VERSION 5.4 ;
NAMESCASESENSITIVE ON ;
BUSBITCHARS "[]" ;
DIVIDERCHAR "/" ;
UNITS
  DATABASE MICRONS 2000 ;
END UNITS
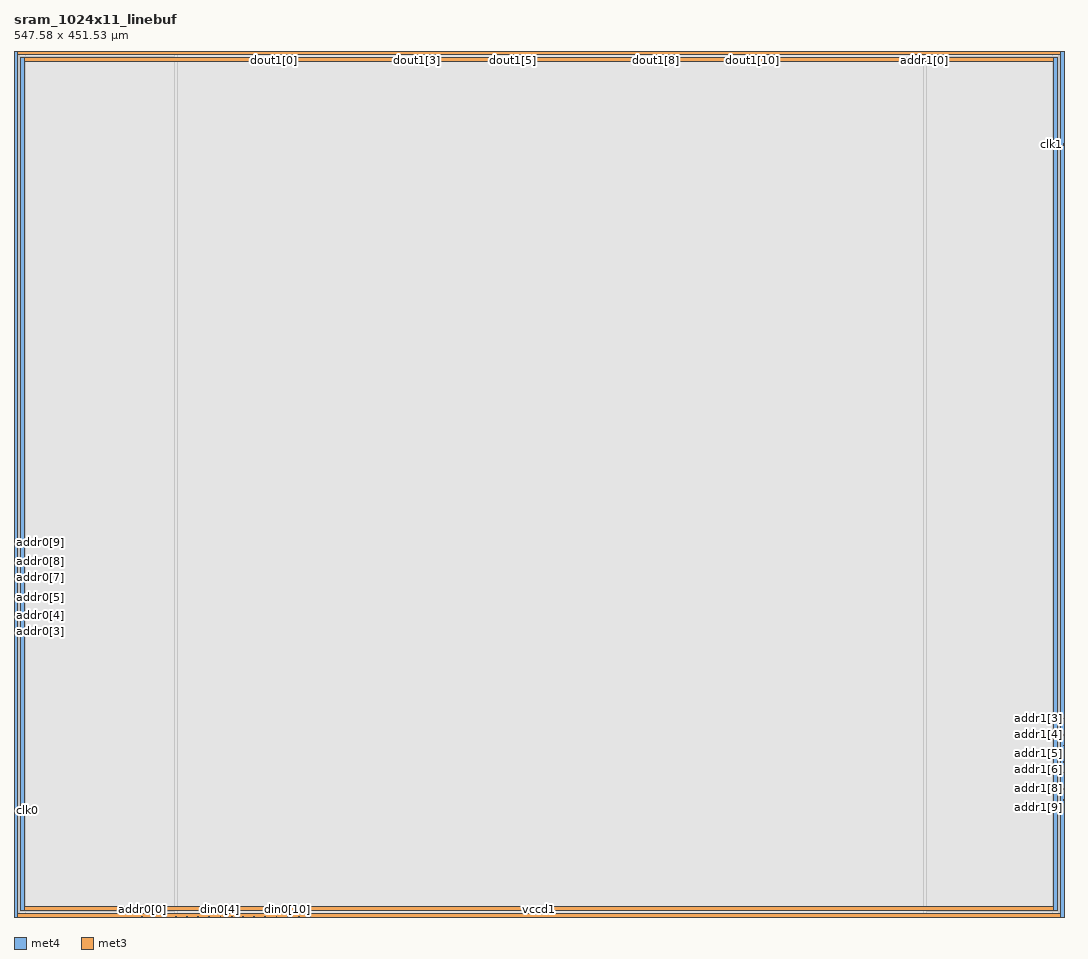
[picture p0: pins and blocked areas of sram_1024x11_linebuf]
MACRO sram_1024x11_linebuf
   CLASS BLOCK ;
   SIZE 547.58 BY 451.53 ;
   SYMMETRY X Y R90 ;
   PIN din0[0]
      DIRECTION INPUT ;
      PORT
         LAYER met4 ;
         RECT  84.14 0.0 84.52 0.38 ;
      END
   END din0[0]
   PIN din0[1]
      DIRECTION INPUT ;
      PORT
         LAYER met4 ;
         RECT  89.98 0.0 90.36 0.38 ;
      END
   END din0[1]
   PIN din0[2]
      DIRECTION INPUT ;
      PORT
         LAYER met4 ;
         RECT  95.82 0.0 96.2 0.38 ;
      END
   END din0[2]
   PIN din0[3]
      DIRECTION INPUT ;
      PORT
         LAYER met4 ;
         RECT  101.66 0.0 102.04 0.38 ;
      END
   END din0[3]
   PIN din0[4]
      DIRECTION INPUT ;
      PORT
         LAYER met4 ;
         RECT  107.5 0.0 107.88 0.38 ;
      END
   END din0[4]
   PIN din0[5]
      DIRECTION INPUT ;
      PORT
         LAYER met4 ;
         RECT  113.34 0.0 113.72 0.38 ;
      END
   END din0[5]
   PIN din0[6]
      DIRECTION INPUT ;
      PORT
         LAYER met4 ;
         RECT  119.18 0.0 119.56 0.38 ;
      END
   END din0[6]
   PIN din0[7]
      DIRECTION INPUT ;
      PORT
         LAYER met4 ;
         RECT  125.02 0.0 125.4 0.38 ;
      END
   END din0[7]
   PIN din0[8]
      DIRECTION INPUT ;
      PORT
         LAYER met4 ;
         RECT  130.86 0.0 131.24 0.38 ;
      END
   END din0[8]
   PIN din0[9]
      DIRECTION INPUT ;
      PORT
         LAYER met4 ;
         RECT  136.7 0.0 137.08 0.38 ;
      END
   END din0[9]
   PIN din0[10]
      DIRECTION INPUT ;
      PORT
         LAYER met4 ;
         RECT  142.54 0.0 142.92 0.38 ;
      END
   END din0[10]
   PIN din0[11]
      DIRECTION INPUT ;
      PORT
         LAYER met4 ;
         RECT  148.38 0.0 148.76 0.38 ;
      END
   END din0[11]
   PIN addr0[0]
      DIRECTION INPUT ;
      PORT
         LAYER met4 ;
         RECT  66.62 0.0 67.0 0.38 ;
      END
   END addr0[0]
   PIN addr0[1]
      DIRECTION INPUT ;
      PORT
         LAYER met4 ;
         RECT  72.46 0.0 72.84 0.38 ;
      END
   END addr0[1]
   PIN addr0[2]
      DIRECTION INPUT ;
      PORT
         LAYER met4 ;
         RECT  78.3 0.0 78.68 0.38 ;
      END
   END addr0[2]
   PIN addr0[3]
      DIRECTION INPUT ;
      PORT
         LAYER met3 ;
         RECT  0.0 148.53 0.38 148.91 ;
      END
   END addr0[3]
   PIN addr0[4]
      DIRECTION INPUT ;
      PORT
         LAYER met3 ;
         RECT  0.0 157.03 0.38 157.41 ;
      END
   END addr0[4]
   PIN addr0[5]
      DIRECTION INPUT ;
      PORT
         LAYER met3 ;
         RECT  0.0 162.67 0.38 163.05 ;
      END
   END addr0[5]
   PIN addr0[6]
      DIRECTION INPUT ;
      PORT
         LAYER met3 ;
         RECT  0.0 171.17 0.38 171.55 ;
      END
   END addr0[6]
   PIN addr0[7]
      DIRECTION INPUT ;
      PORT
         LAYER met3 ;
         RECT  0.0 176.785 0.38 177.165 ;
      END
   END addr0[7]
   PIN addr0[8]
      DIRECTION INPUT ;
      PORT
         LAYER met3 ;
         RECT  0.0 185.185 0.38 185.565 ;
      END
   END addr0[8]
   PIN addr0[9]
      DIRECTION INPUT ;
      PORT
         LAYER met3 ;
         RECT  0.0 190.95 0.38 191.33 ;
      END
   END addr0[9]
   PIN addr1[0]
      DIRECTION INPUT ;
      PORT
         LAYER met4 ;
         RECT  474.74 451.15 475.12 451.53 ;
      END
   END addr1[0]
   PIN addr1[1]
      DIRECTION INPUT ;
      PORT
         LAYER met4 ;
         RECT  468.9 451.15 469.28 451.53 ;
      END
   END addr1[1]
   PIN addr1[2]
      DIRECTION INPUT ;
      PORT
         LAYER met4 ;
         RECT  463.06 451.15 463.44 451.53 ;
      END
   END addr1[2]
   PIN addr1[3]
      DIRECTION INPUT ;
      PORT
         LAYER met3 ;
         RECT  547.2 103.39 547.58 103.77 ;
      END
   END addr1[3]
   PIN addr1[4]
      DIRECTION INPUT ;
      PORT
         LAYER met3 ;
         RECT  547.2 94.89 547.58 95.27 ;
      END
   END addr1[4]
   PIN addr1[5]
      DIRECTION INPUT ;
      PORT
         LAYER met3 ;
         RECT  547.2 89.25 547.58 89.63 ;
      END
   END addr1[5]
   PIN addr1[6]
      DIRECTION INPUT ;
      PORT
         LAYER met3 ;
         RECT  547.2 80.75 547.58 81.13 ;
      END
   END addr1[6]
   PIN addr1[7]
      DIRECTION INPUT ;
      PORT
         LAYER met3 ;
         RECT  547.2 75.11 547.58 75.49 ;
      END
   END addr1[7]
   PIN addr1[8]
      DIRECTION INPUT ;
      PORT
         LAYER met3 ;
         RECT  547.2 66.61 547.58 66.99 ;
      END
   END addr1[8]
   PIN addr1[9]
      DIRECTION INPUT ;
      PORT
         LAYER met3 ;
         RECT  547.2 60.97 547.58 61.35 ;
      END
   END addr1[9]
   PIN csb0
      DIRECTION INPUT ;
      PORT
         LAYER met3 ;
         RECT  0.0 54.72 0.38 55.1 ;
      END
   END csb0
   PIN csb1
      DIRECTION INPUT ;
      PORT
         LAYER met3 ;
         RECT  547.2 403.18 547.58 403.56 ;
      END
   END csb1
   PIN clk0
      DIRECTION INPUT ;
      PORT
         LAYER met3 ;
         RECT  0.0 55.465 0.38 55.845 ;
      END
   END clk0
   PIN clk1
      DIRECTION INPUT ;
      PORT
         LAYER met3 ;
         RECT  547.2 402.435 547.58 402.815 ;
      END
   END clk1
   PIN spare_wen0
      DIRECTION INPUT ;
      PORT
         LAYER met4 ;
         RECT  154.22 0.0 154.6 0.38 ;
      END
   END spare_wen0
   PIN dout1[0]
      DIRECTION OUTPUT ;
      PORT
         LAYER met4 ;
         RECT  135.185 451.15 135.565 451.53 ;
      END
   END dout1[0]
   PIN dout1[1]
      DIRECTION OUTPUT ;
      PORT
         LAYER met4 ;
         RECT  160.145 451.15 160.525 451.53 ;
      END
   END dout1[1]
   PIN dout1[2]
      DIRECTION OUTPUT ;
      PORT
         LAYER met4 ;
         RECT  185.105 451.15 185.485 451.53 ;
      END
   END dout1[2]
   PIN dout1[3]
      DIRECTION OUTPUT ;
      PORT
         LAYER met4 ;
         RECT  210.065 451.15 210.445 451.53 ;
      END
   END dout1[3]
   PIN dout1[4]
      DIRECTION OUTPUT ;
      PORT
         LAYER met4 ;
         RECT  235.025 451.15 235.405 451.53 ;
      END
   END dout1[4]
   PIN dout1[5]
      DIRECTION OUTPUT ;
      PORT
         LAYER met4 ;
         RECT  259.985 451.15 260.365 451.53 ;
      END
   END dout1[5]
   PIN dout1[6]
      DIRECTION OUTPUT ;
      PORT
         LAYER met4 ;
         RECT  284.945 451.15 285.325 451.53 ;
      END
   END dout1[6]
   PIN dout1[7]
      DIRECTION OUTPUT ;
      PORT
         LAYER met4 ;
         RECT  309.905 451.15 310.285 451.53 ;
      END
   END dout1[7]
   PIN dout1[8]
      DIRECTION OUTPUT ;
      PORT
         LAYER met4 ;
         RECT  334.865 451.15 335.245 451.53 ;
      END
   END dout1[8]
   PIN dout1[9]
      DIRECTION OUTPUT ;
      PORT
         LAYER met4 ;
         RECT  359.825 451.15 360.205 451.53 ;
      END
   END dout1[9]
   PIN dout1[10]
      DIRECTION OUTPUT ;
      PORT
         LAYER met4 ;
         RECT  384.785 451.15 385.165 451.53 ;
      END
   END dout1[10]
   PIN dout1[11]
      DIRECTION OUTPUT ;
      PORT
         LAYER met4 ;
         RECT  411.595 451.15 411.975 451.53 ;
      END
   END dout1[11]
   PIN vccd1
      DIRECTION INOUT ;
      USE POWER ; 
      SHAPE ABUTMENT ; 
      PORT
         LAYER met4 ;
         RECT  0.0 0.0 1.74 451.53 ;
         LAYER met4 ;
         RECT  545.84 0.0 547.58 451.53 ;
         LAYER met3 ;
         RECT  0.0 0.0 547.58 1.74 ;
         LAYER met3 ;
         RECT  0.0 449.79 547.58 451.53 ;
      END
   END vccd1
   PIN vssd1
      DIRECTION INOUT ;
      USE GROUND ; 
      SHAPE ABUTMENT ; 
      PORT
         LAYER met4 ;
         RECT  3.48 3.48 5.22 448.05 ;
         LAYER met3 ;
         RECT  3.48 446.31 544.1 448.05 ;
         LAYER met4 ;
         RECT  542.36 3.48 544.1 448.05 ;
         LAYER met3 ;
         RECT  3.48 3.48 544.1 5.22 ;
      END
   END vssd1
   OBS
   LAYER  met1 ;
      RECT  0.62 0.62 546.96 450.91 ;
   LAYER  met2 ;
      RECT  0.62 0.62 546.96 450.91 ;
   LAYER  met3 ;
      RECT  0.98 147.93 546.96 149.51 ;
      RECT  0.62 149.51 0.98 156.43 ;
      RECT  0.62 158.01 0.98 162.07 ;
      RECT  0.62 163.65 0.98 170.57 ;
      RECT  0.62 172.15 0.98 176.185 ;
      RECT  0.62 177.765 0.98 184.585 ;
      RECT  0.62 186.165 0.98 190.35 ;
      RECT  0.98 102.79 546.6 104.37 ;
      RECT  0.98 104.37 546.6 147.93 ;
      RECT  546.6 104.37 546.96 147.93 ;
      RECT  546.6 95.87 546.96 102.79 ;
      RECT  546.6 90.23 546.96 94.29 ;
      RECT  546.6 81.73 546.96 88.65 ;
      RECT  546.6 76.09 546.96 80.15 ;
      RECT  546.6 67.59 546.96 74.51 ;
      RECT  546.6 61.95 546.96 66.01 ;
      RECT  0.98 149.51 546.6 402.58 ;
      RECT  0.98 402.58 546.6 404.16 ;
      RECT  0.62 56.445 0.98 147.93 ;
      RECT  546.6 149.51 546.96 401.835 ;
      RECT  546.6 2.34 546.96 60.37 ;
      RECT  0.62 2.34 0.98 54.12 ;
      RECT  0.62 191.93 0.98 449.19 ;
      RECT  546.6 404.16 546.96 449.19 ;
      RECT  0.98 404.16 2.88 445.71 ;
      RECT  0.98 445.71 2.88 448.65 ;
      RECT  0.98 448.65 2.88 449.19 ;
      RECT  2.88 404.16 544.7 445.71 ;
      RECT  2.88 448.65 544.7 449.19 ;
      RECT  544.7 404.16 546.6 445.71 ;
      RECT  544.7 445.71 546.6 448.65 ;
      RECT  544.7 448.65 546.6 449.19 ;
      RECT  0.98 2.34 2.88 2.88 ;
      RECT  0.98 2.88 2.88 5.82 ;
      RECT  0.98 5.82 2.88 102.79 ;
      RECT  2.88 2.34 544.7 2.88 ;
      RECT  2.88 5.82 544.7 102.79 ;
      RECT  544.7 2.34 546.6 2.88 ;
      RECT  544.7 2.88 546.6 5.82 ;
      RECT  544.7 5.82 546.6 102.79 ;
   LAYER  met4 ;
      RECT  83.54 0.98 85.12 450.91 ;
      RECT  85.12 0.62 89.38 0.98 ;
      RECT  90.96 0.62 95.22 0.98 ;
      RECT  96.8 0.62 101.06 0.98 ;
      RECT  102.64 0.62 106.9 0.98 ;
      RECT  108.48 0.62 112.74 0.98 ;
      RECT  114.32 0.62 118.58 0.98 ;
      RECT  120.16 0.62 124.42 0.98 ;
      RECT  126.0 0.62 130.26 0.98 ;
      RECT  131.84 0.62 136.1 0.98 ;
      RECT  137.68 0.62 141.94 0.98 ;
      RECT  143.52 0.62 147.78 0.98 ;
      RECT  67.6 0.62 71.86 0.98 ;
      RECT  73.44 0.62 77.7 0.98 ;
      RECT  79.28 0.62 83.54 0.98 ;
      RECT  85.12 0.98 474.14 450.55 ;
      RECT  474.14 0.98 475.72 450.55 ;
      RECT  469.88 450.55 474.14 450.91 ;
      RECT  464.04 450.55 468.3 450.91 ;
      RECT  149.36 0.62 153.62 0.98 ;
      RECT  85.12 450.55 134.585 450.91 ;
      RECT  136.165 450.55 159.545 450.91 ;
      RECT  161.125 450.55 184.505 450.91 ;
      RECT  186.085 450.55 209.465 450.91 ;
      RECT  211.045 450.55 234.425 450.91 ;
      RECT  236.005 450.55 259.385 450.91 ;
      RECT  260.965 450.55 284.345 450.91 ;
      RECT  285.925 450.55 309.305 450.91 ;
      RECT  310.885 450.55 334.265 450.91 ;
      RECT  335.845 450.55 359.225 450.91 ;
      RECT  360.805 450.55 384.185 450.91 ;
      RECT  385.765 450.55 410.995 450.91 ;
      RECT  412.575 450.55 462.46 450.91 ;
      RECT  2.34 0.62 66.02 0.98 ;
      RECT  475.72 450.55 545.24 450.91 ;
      RECT  155.2 0.62 545.24 0.98 ;
      RECT  2.34 0.98 2.88 2.88 ;
      RECT  2.34 2.88 2.88 448.65 ;
      RECT  2.34 448.65 2.88 450.91 ;
      RECT  2.88 0.98 5.82 2.88 ;
      RECT  2.88 448.65 5.82 450.91 ;
      RECT  5.82 0.98 83.54 2.88 ;
      RECT  5.82 2.88 83.54 448.65 ;
      RECT  5.82 448.65 83.54 450.91 ;
      RECT  475.72 0.98 541.76 2.88 ;
      RECT  475.72 2.88 541.76 448.65 ;
      RECT  475.72 448.65 541.76 450.55 ;
      RECT  541.76 0.98 544.7 2.88 ;
      RECT  541.76 448.65 544.7 450.55 ;
      RECT  544.7 0.98 545.24 2.88 ;
      RECT  544.7 2.88 545.24 448.65 ;
      RECT  544.7 448.65 545.24 450.55 ;
   END
END    sram_1024x11_linebuf
END    LIBRARY
